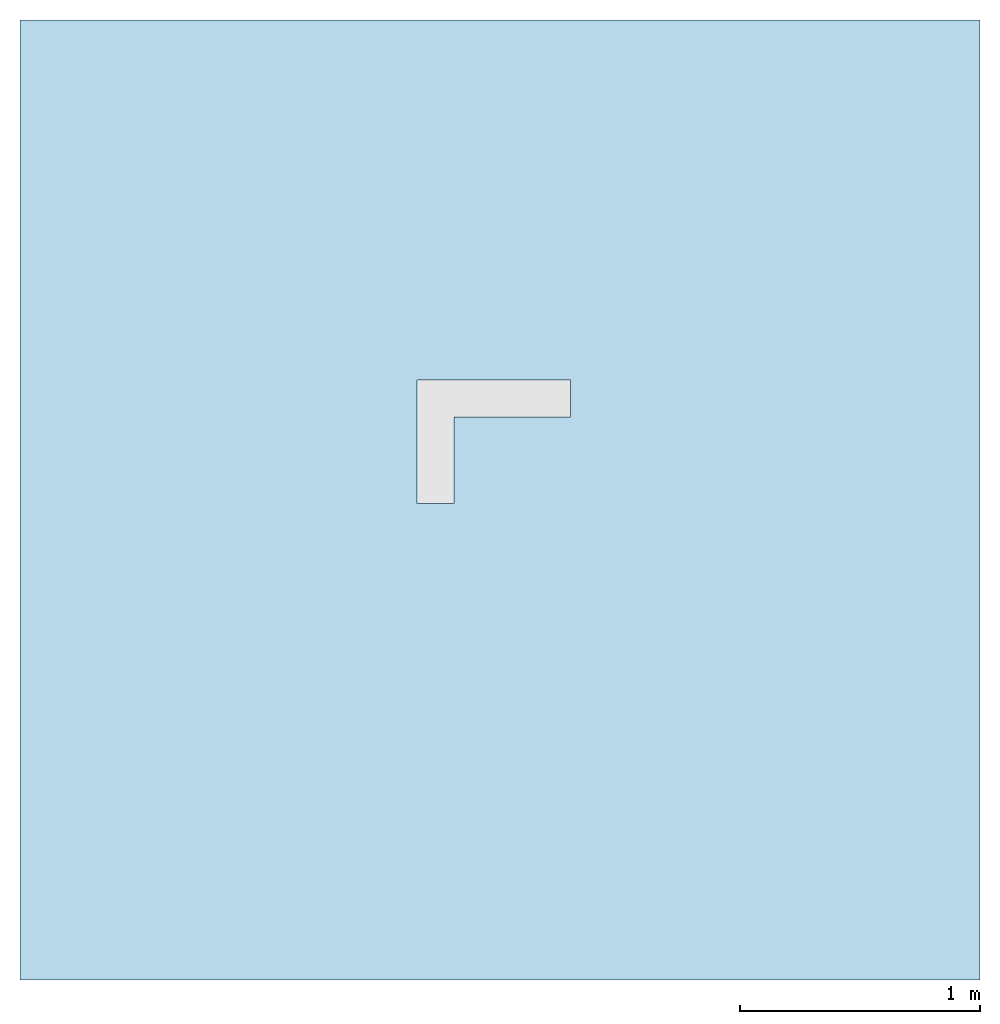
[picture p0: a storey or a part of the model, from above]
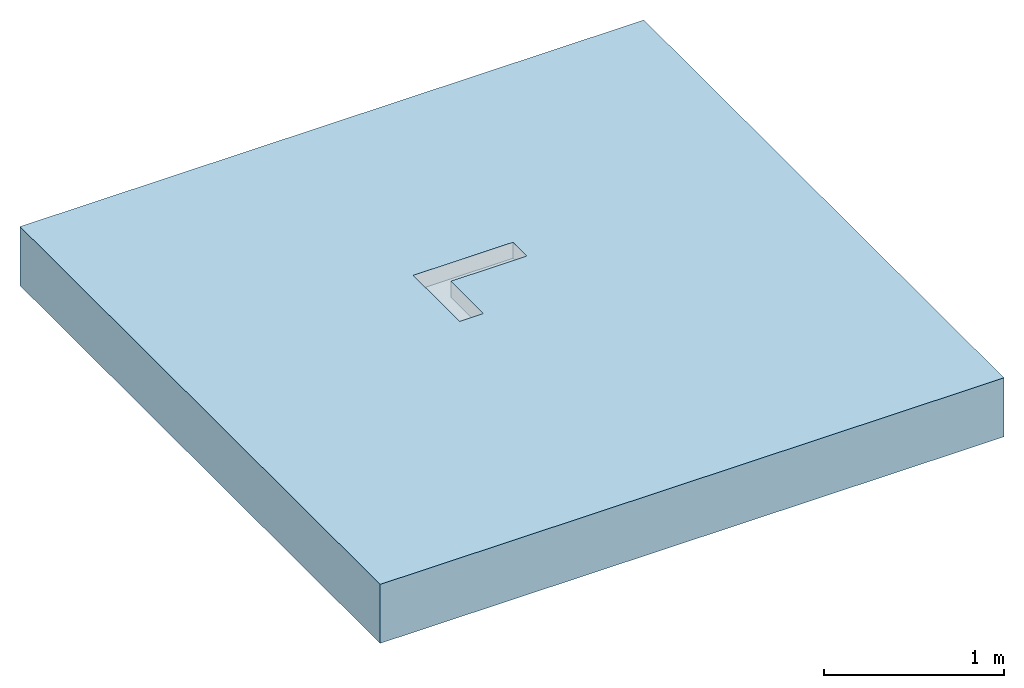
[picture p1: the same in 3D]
Properties of the parts of a building model (IFC2X3)

# File
Description: ViewDefinition [CoordinationView]
File name: 105210 - Corner Unit Channel - Right Hand - 500mm LG - Invert Depth 95mm.ifc
Time: 2014-03-20T10:13:19
Written by: Autodesk Revit 2013
Made in: 20120221_2030(x64)

# IfcProject, Project Number
LongName: Project Name; Phase: Project Status

# IfcSite, Default
RefLatitude: 42, 21, 30, 344238; RefLongitude: -71, -3, -35, -194702; RefElevation: 0 mm

# IfcBuilding
Pset_BuildingCommon - NumberOfStoreys: 1
Other - Client Name: Owner; Project Address: ## Street City, State Zip; Project Number: Project Number; Project Name: Project Name; Project Issue Date: Issue Date; Project Status: Project Status

# IfcBuildingStorey, Level 1
LongName: Level 1; Elevation: 0 mm
Constraints - Elevation Base: 0; Elevation: 0 mm
Graphics - Line Pattern: Center; Symbol at End 2 Default: yes; Line Weight: 1; Symbol: M_Level Head - Circle: M_Level Head - Circle; Symbol at End 1 Default: no; Color: 0
Dimensions - Computation Height: 0 mm
Identity Data - Name: Level 1; Structural: no; Building Story: yes

# IfcFlowTerminal: 105210 - Corner Unit Channel - Right Hand - 500mm LG - Invert Depth 95mm, ACO BD Modular 125 Corner Units:105210 - Corner Unit Channel - Right Hand - 500mm LG - Invert Depth 95mm:105210 - Corner Unit Channel - Right Hand - 500mm LG - Invert Depth 95mm:213559
In: Level 1
Material: Stainless Steel AISI 304 (F), Polystyrene, High Impact (F)
Construction - 105844 - Slip Resistant Quadrato Locked - Stainless Steel 304 - 500mm long: no; 105521 - Slotted Locked - Stainless Steel 304 - 500mm long: no; 105539 - Intercept - Stainless Steel 304 - 500mm long: no; End Plate Invert: no; 21710 - Grating - Slip Resistant Mesh - Stainless Steel 304 - 500mm long: no; 105505 - Perforated Locked - Stainless Steel 304 - 500mm long: no; 105528 - Quadrato Locked - Stainless Steel 304 - 500mm long: no; 105842 - Slip Resistant Quadrato - Stainless Steel 304 - 500mm long: no; 21720 - Grating - Plain Mesh - Stainless Steel 304 - 500mm long: no; End Plate Invert Left: no; 96819 - Grating - Heal Safe - Stainless Steel 304 - 500mm long: no; 402072- Grating - Heal Safe Locked - Stainless Steel 304 - 500mm long: no; 49061 & 49062_Vinyl Seal: no; 21920 - Grating - Plain Mesh - Stainless Steel 304 - 500mm long: no; 21790 - Plastic - White Plastic - 500mm long: no; 26270_PVC Infill: yes; 105519 - Slotted Locked - Stainless Steel 304 - 500mm long: no; 105530 - Quadrato - Stainless Steel 304 - 500mm long: no; 105846 - Slip Resistant Intercept - Stainless Steel 304 - 500mm long: no; 105537 - Intercept Locked - Stainless Steel 304 - 500mm long: no; 105848 - Slip Resistant Intercept Locked - Stainless Steel 304 - 500mm long: no; End Plate Invert Right: no; 15704 - Composite - Black Composite - 500mm long: no; 21740 - - Ladder - Stainless Steel 304 - 500mm long: no; 21910 - Grating - Slip Resistant Mesh - Stainless Steel 304 - 500mm long: no; 10735 - Composite - White Composite - 500mm long: no; Detail 95mm: yes; Connecting Plate (Right): yes; Detail 110mm: no; Grating (Left): no; Detail 65mm: no; Left Hand Corner Unit: no; Detail 125mm: no; Detail 80mm: no; Connecting Plate (Left): no; Right Hand Corner Unit: yes; Grating (Right): yes; Grating: yes; Detail 50mm: no
Constraints - Level: Level: Level 1; Moves With Nearby Elements: no
Other - Rigid PVC Extrusion (49061): 0 mm; Flexible PVC Seal (49062): 0 mm; Neoprene Gasket: 1; PVC Infill (26270): 2000 mm; Detail H: 106.3 mm
Identity Data - Mark: 2; Manufacturer: ACO Building Drainage; Address: ACO Business Centre, Caxton Road, Bedford, MK41 0LF; Telephone: +44 (0)1462 816666; Watermark1: This file is the property of ACO Technologies PLC; Fax: +44 (0)1462 851490; Watermark2: This file is water marked and users are prohibited to reproduce, adapt, distribute this information; Watermarked By: www.acobd.com; E-mail Technical: abdtechnical@aco.co.uk; Website: www.acobd.com; E-mail Sales: abdcommercial@aco.co.uk; Watermarked With: BIM Manager Premium Suite
Phasing - Phase Created: New Construction
Model Properties - Grating Product Code 105521: Load Class C250 - Slotted Locked - Stainless Steel 304 - 500mm long - 2.3kg; Grating Product Code 402072: Load Class B125 - Heal Safe Locked - Stainless Steel 304 - 500mm long - 2.0kg; Grating Product Code 105519: Load Class A15 - Slotted Locked - Stainless Steel 304 - 500mm long - 1.0kg; End Plate Product Code 105104: N/A; Grating Product Code 21740: Load Class C250 - Ladder - Stainless Steel 304 - 500mm long - 2.0kg; Grating Product Code 21920: Load Class C250 - Plain Mesh - Stainless Steel 304 - 500mm long - 2.2kg; Grating Product Code 105539: Load Class A15 - Intercept - Stainless Steel 304 - 500mm long - 1.8kg; Grating Product Code 105505: Load Class C250 - Perforated Locked - Stainless Steel 304 - 500mm long - 1.8kg; Grating Product Code 105848: Load Class A15 - Slip Resistant Intercept Locked - Stainless Steel 304 - 500mm long - 1.8kg; Grating Product Code 21790: Load Class A15 - Plastic - White Plastic - 500mm long - 0.6kg; Grating Product Code 15704: Load Class C250 - Composite - Black Composite - 500mm long - 1.2kg; Grating Product Code 105530: Load Class A15 - Quadrato - Stainless Steel 304 - 500mm long - 1.6kg; End Plate Product Code 105103: End Plate Stainless Steel 304 for Invert Depth - 95mm - 0.24Kg; Grating Product Code 21710: Load Class A15 - Slip Resistant Mesh - Stainless Steel 304 - 500mm long - 1.6kg; Grating Product Code 10735: Load Class C250 - Composite - White Composite - 500mm long - 1.2kg; End Plate Product Code 105101: N/A; Grating Product Code 105528: Load Class A15 - Quadrato Locked - Stainless Steel 304 - 500mm long - 1.6kg; Grating Product Code 96819: Load Class B125 - Heal Safe - Stainless Steel 304 - 500mm long - 2.0kg; Grating Product Code 105846: Load Class A15 - Slip Resistant Intercept - Stainless Steel 304 - 500mm long - 1.8kg; Grating Product Code 21720: Load Class A15 - Plain Mesh - Stainless Steel 304 - 500mm long - 1.6kg; End Plate Product Code 105100: N/A; Grating Product Code 105842: Load Class A15 - Slip Resistant Quadrato - Stainless Steel 304 - 500mm long - 1.6kg; End Plate Product Code 105102: N/A; Grating Product Code 105844: Load Class A15 - Slip Resistant Quadrato Locked - Stainless Steel 304 - 500mm long - 1.6kg; End Plate Product Code 105105: N/A; Grating Product Code 21910: Load Class C250 - Slip Resistant Mesh - Stainless Steel 304 - 500mm long - 2.2kg; Grating Product Code 105537: Load Class A15 - Intercept Locked - Stainless Steel 304 - 500mm long - 1.8kg
Dimensions - Floor Void Depth: 107.8 mm; Grating Height: 21 mm; Invert Depth: 95 mm; Angle: 90 deg; Endplate V Length: 1139 mm; Depth: 74 mm
General - Maintenance guidelines: X:\Electronic Literature\ABD Electronic Literature\Standard Stainless Steel and Galvanised Steel Channels\ACO Modular 125\ACO Modular 125.pdf; Weight (Kg): 5.1; Product Code: 105210; Channel Colour: Mid Grey; Seal Colour: Black; Seal Recycled Material Content: 0%; Dimensions (LxWxH): 500 x 514 x 95; Product Description: ACO Modular 125 500mm Corner Unit Right Hand; Seal Material: Neoprene; Channel Material: Stainless Steel Grade 304; Channel Recyclable: Fully recyclable; Product Standard: BS EN 1433:2002, CE marked; NBS Specification: NBS Section Q10 Kerbs/edgings/channels/paving accessories, Clause 180 Drainage Channel Systems; Channel Recycled Material Content: 60-70%; Installation guidelines: X:\Electronic Literature\ABD Electronic Literature\Standard Stainless Steel and Galvanised Steel Channels\ACO Modular 125\ACO Modular 125.pdf; Seal Recyclable: Fully recyclable; Load Class: A15 - C250; Price: POA - contact ACO; Product Range: ACO Modular 125; Product Type: Stainless Steel Channel Drainage System

# IfcOpeningElement: Recess
In: Level 1
Constraints - Height Offset From Level: 0 mm; Level: Level: Level 1; Room Bounding: yes; Related to Mass: no
Structural - Enable Analytical Model: no; Structural: no
Phasing - Phase Created: New Construction
Dimensions - Volume: 6383506600 mm3; Area: 16000000 mm2; Perimeter: 16000 mm; Thickness: 400 mm
Analytical Properties - Heat Transfer Coefficient (U): 2.615; Thermal Resistance (R): 0.382409; Thermal mass: 604440; Absorptance: 0.1; Roughness: 1
Materials and Finishes - Structural Material: Concrete, Broom Finish
Construction - Default Thickness: 400 mm; Function: 0
Graphics - Coarse Scale Fill Color: 0

# IfcSlab: Floor:Generic Floor - 400mm, Floor:Generic Floor - 400mm:193825
In: Level 1
PredefinedType: FLOOR; Material: Concrete, Broom Finish 400 mm
Constraints - Height Offset From Level: 0 mm; Level: Level: Level 1; Room Bounding: yes; Related to Mass: no
Structural - Enable Analytical Model: no; Structural: no
Phasing - Phase Created: New Construction
Dimensions - Volume: 6383506600 mm3; Area: 16000000 mm2; Perimeter: 16000 mm; Thickness: 400 mm
Pset_SlabCommon - Reference: Generic Floor - 400mm; IsExternal: no; LoadBearing: yes
Analytical Properties - Heat Transfer Coefficient (U): 2.615; Thermal Resistance (R): 0.382409; Thermal mass: 604440; Absorptance: 0.1; Roughness: 1
Materials and Finishes - Structural Material: Concrete, Broom Finish
Construction - Default Thickness: 400 mm; Function: 0
Graphics - Coarse Scale Fill Color: 0
